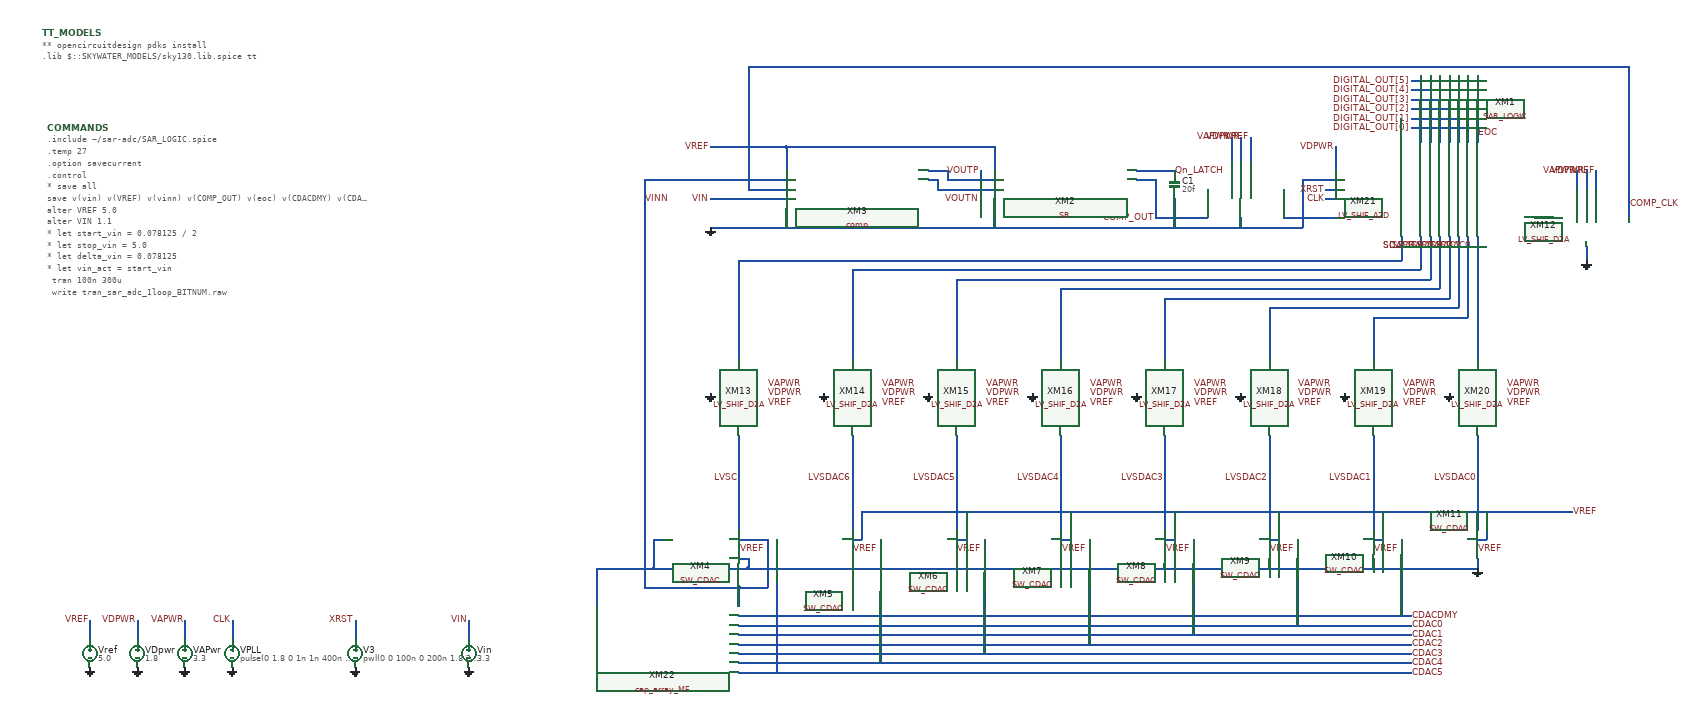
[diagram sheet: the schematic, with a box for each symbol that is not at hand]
v {xschem version=3.4.8RC file_version=1.3}
G {}
K {}
V {}
S {}
F {}
E {}
N 330 -310 330 -270 {
lab=VAPWR}
N 430 -310 430 -270 {
lab=CLK}
N 690 -310 690 -270 {
lab=XRST}
N 3050 -1100 3060 -1100 {
lab=SDAC0}
N 3030 -1100 3040 -1100 {
lab=SDAC1}
N 3010 -1100 3020 -1100 {
lab=SDAC2}
N 2990 -1100 3000 -1100 {
lab=SDAC3}
N 2970 -1100 2980 -1100 {
lab=SDAC4}
N 2950 -1100 2960 -1100 {
lab=SDAC5}
N 2930 -1100 2940 -1100 {
lab=SDAC6}
N 2890 -1100 2900 -1100 {
lab=SC}
N 930 -310 930 -270 {
lab=VIN}
N 2010 -1220 2010 -1200 {
lab=VOUTN}
N 2010 -1260 2010 -1240 {
lab=VOUTP}
N 230 -310 230 -270 {
lab=VDPWR}
N 130 -310 130 -270 {
lab=VREF}
N 2740 -1200 2760 -1200 {
lab=CLK}
N 2740 -1220 2760 -1220 {
lab=XRST}
N 1900 -1260 1940 -1260 {
lab=VOUTP}
N 1900 -1240 1920 -1240 {
lab=VOUTN}
N 1500 -320 2920 -320 {
lab=CDACDMY}
N 1500 -300 2920 -300 {
lab=CDAC0}
N 1500 -280 2920 -280 {
lab=CDAC1}
N 1500 -260 2920 -260 {
lab=CDAC2}
N 1500 -240 2920 -240 {
lab=CDAC3}
N 1500 -220 2920 -220 {
lab=CDAC4}
N 1500 -200 2920 -200 {
lab=CDAC5}
N 1740 -680 1740 -500 {
lab=LVSDAC6}
N 1960 -660 1960 -500 {
lab=LVSDAC5}
N 2180 -640 2180 -500 {
lab=LVSDAC4}
N 2400 -620 2400 -500 {
lab=LVSDAC3}
N 2620 -600 2620 -500 {
lab=LVSDAC2}
N 2840 -580 2840 -500 {
lab=LVSDAC1}
N 3060 -690 3060 -500 {
lab=LVSDAC0}
N 1500 -700 1500 -500 {
lab=LVSC}
N 1320 -480 1340 -480 {
lab=GND}
N 1320 -480 1320 -420 {
lab=GND}
N 1320 -420 1520 -420 {
lab=GND}
N 1520 -440 1520 -420 {
lab=GND}
N 1500 -440 1520 -440 {
lab=GND}
N 1500 -380 1500 -340 {
lab=VINN}
N 1300 -380 1500 -380 {
lab=VINN}
N 1300 -900 1300 -380 {
lab=VINN}
N 1500 -480 1560 -480 {
lab=VINN}
N 1560 -480 1560 -380 {
lab=VINN}
N 1500 -380 1560 -380 {
lab=VINN}
N 1520 -1220 1600 -1220 {
lab=COMP_CLK}
N 1620 -1480 3380 -1480 {
lab=COMP_CLK}
N 3380 -1480 3380 -1160 {
lab=COMP_CLK}
N 2340 -1240 2380 -1240 {
lab=COMP_OUT}
N 2380 -1240 2380 -1160 {
lab=COMP_OUT}
N 2340 -1260 2420 -1260 {
lab=Qn_LATCH}
N 1760 -540 3260 -540 {
lab=VREF}
N 1740 -480 1760 -480 {
lab=VREF}
N 1760 -540 1760 -480 {
lab=VREF}
N 1960 -480 1980 -480 {
lab=VREF}
N 1980 -540 1980 -480 {
lab=VREF}
N 2180 -480 2200 -480 {
lab=VREF}
N 2200 -540 2200 -480 {
lab=VREF}
N 2400 -480 2420 -480 {
lab=VREF}
N 2420 -540 2420 -480 {
lab=VREF}
N 2620 -480 2640 -480 {
lab=VREF}
N 2640 -540 2640 -480 {
lab=VREF}
N 2840 -480 2860 -480 {
lab=VREF}
N 2860 -540 2860 -480 {
lab=VREF}
N 3060 -480 3080 -480 {
lab=VREF}
N 3080 -540 3080 -480 {
lab=VREF}
N 1940 -1260 1940 -1240 {
lab=VOUTP}
N 2020 -480 2020 -240 {
lab=CDAC3}
N 1800 -480 1800 -220 {
lab=CDAC4}
N 1580 -480 1580 -200 {
lab=CDAC5}
N 2940 -1460 2940 -1320 {
lab=DIGITAL_OUT[5]}
N 2960 -1460 2960 -1320 {
lab=DIGITAL_OUT[4]}
N 2980 -1460 2980 -1320 {
lab=DIGITAL_OUT[3]}
N 3000 -1460 3000 -1320 {
lab=DIGITAL_OUT[2]}
N 3020 -1460 3020 -1320 {
lab=DIGITAL_OUT[1]}
N 3040 -1460 3040 -1320 {
lab=DIGITAL_OUT[0]}
N 3060 -1460 3060 -1320 {
lab=EOC}
N 1920 -1240 1920 -1220 {
lab=VOUTN}
N 1920 -1220 2040 -1220 {
lab=VOUTN}
N 1940 -1240 2040 -1240 {
lab=VOUTP}
N 2760 -1310 2760 -1260 {lab=VDPWR}
N 2040 -1310 2040 -1260 {lab=VREF}
N 1600 -1310 1600 -1260 {lab=VREF}
N 1590 -1140 2590 -1140 {lab=GND}
N 2690 -1240 2760 -1240 {lab=GND}
N 2420 -1200 2420 -1140 {lab=GND}
N 2040 -1200 2040 -1140 {lab=GND}
N 1600 -1180 1600 -1140 {lab=GND}
N 1520 -420 3060 -420 {lab=GND}
N 3060 -440 3060 -420 {lab=GND}
N 1740 -440 1740 -420 {lab=GND}
N 1960 -440 1960 -420 {lab=GND}
N 2180 -440 2180 -420 {lab=GND}
N 2400 -440 2400 -420 {lab=GND}
N 2620 -440 2620 -420 {lab=GND}
N 1440 -1310 1580 -1310 {lab=VREF}
N 1490 -1200 1600 -1200 {lab=VIN}
N 1440 -1200 1490 -1200 {lab=VIN}
N 1440 -1140 1590 -1140 {lab=GND}
N 1200 -420 1320 -420 {lab=GND}
N 1200 -420 1200 -340 {lab=GND}
N 1580 -1310 1600 -1310 {lab=VREF}
N 1600 -1310 2040 -1310 {lab=VREF}
N 3180 -1160 3220 -1160 {lab=#net1}
N 3060 -700 3060 -690 {lab=LVSDAC0}
N 2840 -700 2840 -580 {lab=LVSDAC1}
N 2620 -700 2620 -600 {lab=LVSDAC2}
N 2400 -700 2400 -620 {lab=LVSDAC3}
N 2180 -700 2180 -640 {lab=LVSDAC4}
N 1960 -700 1960 -660 {lab=LVSDAC5}
N 1740 -700 1740 -680 {lab=LVSDAC6}
N 1500 -1070 1500 -860 {lab=SC}
N 1500 -1070 2900 -1070 {lab=SC}
N 2900 -1120 2900 -1070 {lab=SC}
N 1740 -1050 1740 -860 {lab=SDAC6}
N 1740 -1050 2940 -1050 {lab=SDAC6}
N 2940 -1120 2940 -1050 {lab=SDAC6}
N 1960 -1030 1960 -860 {lab=SDAC5}
N 1960 -1030 2960 -1030 {lab=SDAC5}
N 2960 -1120 2960 -1030 {lab=SDAC5}
N 2180 -1010 2180 -860 {lab=SDAC4}
N 2180 -1010 2980 -1010 {lab=SDAC4}
N 2980 -1120 2980 -1010 {lab=SDAC4}
N 2400 -990 2400 -860 {lab=SDAC3}
N 2400 -990 3000 -990 {lab=SDAC3}
N 3000 -1120 3000 -990 {lab=SDAC3}
N 2620 -970 2620 -860 {lab=SDAC2}
N 2620 -970 3020 -970 {lab=SDAC2}
N 3020 -1120 3020 -970 {lab=SDAC2}
N 2840 -950 2840 -860 {lab=SDAC1}
N 2840 -950 3040 -950 {lab=SDAC1}
N 3040 -1120 3040 -950 {lab=SDAC1}
N 3060 -1120 3060 -860 {lab=SDAC0}
N 1300 -1240 1300 -900 {lab=VINN}
N 1300 -1240 1600 -1240 {lab=VINN}
N 1520 -1480 1520 -1220 {lab=COMP_CLK}
N 1520 -1480 1620 -1480 {lab=COMP_CLK}
N 2690 -1240 2690 -1140 {lab=GND}
N 2590 -1140 2690 -1140 {lab=GND}
N 2650 -1220 2650 -1160 {lab=#net2}
N 2650 -1160 2760 -1160 {lab=#net2}
N 2490 -1220 2490 -1160 {lab=COMP_OUT}
N 2380 -1160 2490 -1160 {lab=COMP_OUT}
N 2540 -1330 2540 -1280 {lab=VAPWR}
N 2560 -1330 2560 -1280 {lab=VDPWR}
N 2580 -1330 2580 -1280 {lab=VREF}
N 3270 -1260 3270 -1220 {lab=VAPWR}
N 3290 -1260 3290 -1220 {lab=VDPWR}
N 3310 -1260 3310 -1220 {lab=VREF}
N 2560 -1160 2560 -1140 {lab=GND}
N 3290 -1100 3290 -1070 {lab=GND}
N 2920 -1350 3040 -1350 {lab=DIGITAL_OUT[0]}
N 2920 -1370 3020 -1370 {lab=DIGITAL_OUT[1]}
N 2920 -1390 3000 -1390 {lab=DIGITAL_OUT[2]}
N 2920 -1410 2980 -1410 {lab=DIGITAL_OUT[3]}
N 2920 -1430 2960 -1430 {lab=DIGITAL_OUT[4]}
N 2920 -1450 2940 -1450 {lab=DIGITAL_OUT[5]}
N 2460 -480 2460 -280 {lab=CDAC1}
N 2240 -480 2240 -260 {lab=CDAC2}
N 2680 -480 2680 -300 {lab=CDAC0}
N 2900 -480 2900 -320 {lab=CDACDMY}
N 2840 -440 2840 -420 {lab=GND}
C {devices/vsource.sym} 330 -240 0 0 {name=VAPwr value=3.3 savecurrent=false}
C {devices/gnd.sym} 430 -210 0 0 {name=l2 lab=GND}
C {devices/gnd.sym} 330 -210 0 0 {name=l3 lab=GND}
C {devices/simulator_commands_shown.sym} 40 -1350 0 0 {name=COMMANDS
simulator=ngspice
only_toplevel=false 
value=".include ~/sar-adc/SAR_LOGIC.spice
.temp 27
.option savecurrent
.control
* save all
save v(vin) v(VREF) v(vinn) v(COMP_OUT) v(eoc) v(CDACDMY) v(CDAC0) v(CDAC1) v(CDAC2) v(CDAC3) v(CDAC4) v(CDAC5) v(digital_out[5]) v(digital_out[4]) v(digital_out[3]) v(digital_out[2]) v(digital_out[1]) v(digital_out[0])

alter VREF 5.0
alter VIN  1.1

* let start_vin = 0.078125 / 2
* let stop_vin = 5.0
* let delta_vin = 0.078125
* let vin_act = start_vin

	tran 100n 300u
	write tran_sar_adc_1loop_BITNUM.raw
	meas tran vin FIND v(VIN) WHEN v(EOC)=0.9 FALL=LAST
	meas tran vinn FIND v(vinn) WHEN v(EOC)=0.9 FALL=LAST
	meas tran vout5 FIND v(DIGITAL_OUT[5]) WHEN v(EOC)=0.9 FALL=LAST
	meas tran vout4 FIND v(DIGITAL_OUT[4]) WHEN v(EOC)=0.9 FALL=LAST
	meas tran vout3 FIND v(DIGITAL_OUT[3]) WHEN v(EOC)=0.9 FALL=LAST
	meas tran vout2 FIND v(DIGITAL_OUT[2]) WHEN v(EOC)=0.9 FALL=LAST
	meas tran vout1 FIND v(DIGITAL_OUT[1]) WHEN v(EOC)=0.9 FALL=LAST
	meas tran vout0 FIND v(DIGITAL_OUT[0]) WHEN v(EOC)=0.9 FALL=LAST
	print vin >> tran_sar_adc_1loop_out_typ_BITNUM.txt
	print vout5 >> tran_sar_adc_1loop_out_typ_BITNUM.txt
	print vout4 >> tran_sar_adc_1loop_out_typ_BITNUM.txt
	print vout3 >> tran_sar_adc_1loop_out_typ_BITNUM.txt
	print vout2 >> tran_sar_adc_1loop_out_typ_BITNUM.txt
	print vout1 >> tran_sar_adc_1loop_out_typ_BITNUM.txt
	print vout0 >> tran_sar_adc_1loop_out_typ_BITNUM.txt

.endc
"}
C {devices/lab_pin.sym} 430 -310 0 0 {name=p2 sig_type=std_logic lab=CLK}
C {devices/lab_pin.sym} 690 -310 0 0 {name=p9 sig_type=std_logic lab=XRST}
C {devices/gnd.sym} 690 -210 0 0 {name=l1 lab=GND}
C {devices/lab_pin.sym} 3050 -1100 3 0 {name=p10 sig_type=std_logic lab=SDAC0}
C {devices/lab_pin.sym} 3030 -1100 3 0 {name=p11 sig_type=std_logic lab=SDAC1}
C {devices/lab_pin.sym} 3010 -1100 3 0 {name=p12 sig_type=std_logic lab=SDAC2}
C {devices/lab_pin.sym} 2990 -1100 3 0 {name=p13 sig_type=std_logic lab=SDAC3}
C {devices/lab_pin.sym} 2970 -1100 3 0 {name=p14 sig_type=std_logic lab=SDAC4}
C {devices/lab_pin.sym} 2950 -1100 3 0 {name=p15 sig_type=std_logic lab=SDAC5}
C {devices/lab_pin.sym} 2930 -1100 3 0 {name=p16 sig_type=std_logic lab=SDAC6}
C {devices/lab_pin.sym} 2890 -1100 3 0 {name=p19 sig_type=std_logic lab=SC}
C {devices/lab_pin.sym} 3380 -1190 2 0 {name=p20 sig_type=std_logic lab=COMP_CLK}
C {devices/gnd.sym} 1440 -1140 0 1 {name=l19 lab=GND}
C {devices/lab_pin.sym} 930 -310 2 1 {name=p25 sig_type=std_logic lab=VIN}
C {devices/gnd.sym} 930 -210 0 0 {name=l22 lab=GND}
C {devices/vsource.sym} 930 -240 0 0 {name=Vin value=3.3 savecurrent=false}
C {devices/lab_pin.sym} 1440 -1200 0 0 {name=p26 sig_type=std_logic lab=VIN}
C {devices/lab_pin.sym} 2010 -1200 0 0 {name=p27 sig_type=std_logic lab=VOUTN}
C {devices/lab_pin.sym} 2010 -1260 2 1 {name=p28 sig_type=std_logic lab=VOUTP}
C {devices/lab_pin.sym} 2920 -260 0 1 {name=p29 sig_type=std_logic lab=CDAC2}
C {devices/lab_pin.sym} 2920 -280 0 1 {name=p30 sig_type=std_logic lab=CDAC1}
C {devices/lab_pin.sym} 2920 -300 0 1 {name=p31 sig_type=std_logic lab=CDAC0}
C {devices/lab_pin.sym} 2920 -320 0 1 {name=p32 sig_type=std_logic lab=CDACDMY}
C {devices/lab_pin.sym} 2920 -240 0 1 {name=p33 sig_type=std_logic lab=CDAC3}
C {devices/lab_pin.sym} 2920 -220 0 1 {name=p34 sig_type=std_logic lab=CDAC4}
C {devices/lab_pin.sym} 2920 -200 0 1 {name=p35 sig_type=std_logic lab=CDAC5}
C {devices/lab_pin.sym} 1300 -1200 0 1 {name=p36 sig_type=std_logic lab=VINN}
C {devices/lab_pin.sym} 2420 -1260 2 0 {name=p38 sig_type=std_logic lab=Qn_LATCH}
C {devices/lab_pin.sym} 2380 -1160 0 0 {name=p39 sig_type=std_logic lab=COMP_OUT}
C {devices/lab_pin.sym} 2920 -1450 0 0 {name=p18 sig_type=std_logic lab=DIGITAL_OUT[5]}
C {devices/lab_pin.sym} 2920 -1430 0 0 {name=p21 sig_type=std_logic lab=DIGITAL_OUT[4]}
C {devices/lab_pin.sym} 2920 -1410 0 0 {name=p40 sig_type=std_logic lab=DIGITAL_OUT[3]}
C {devices/lab_pin.sym} 2920 -1390 0 0 {name=p41 sig_type=std_logic lab=DIGITAL_OUT[2]}
C {devices/lab_pin.sym} 2920 -1370 0 0 {name=p42 sig_type=std_logic lab=DIGITAL_OUT[1]}
C {devices/lab_pin.sym} 2920 -1350 0 0 {name=p43 sig_type=std_logic lab=DIGITAL_OUT[0]}
C {devices/lab_pin.sym} 3060 -1340 2 0 {name=p17 sig_type=std_logic lab=EOC}
C {devices/vsource.sym} 130 -240 0 0 {name=Vref value=5.0 savecurrent=false}
C {devices/gnd.sym} 130 -210 0 0 {name=l23 lab=GND}
C {devices/code.sym} 30 -1550 0 0 {name=TT_MODELS
only_toplevel=true
format="tcleval( @value )"
value="
** opencircuitdesign pdks install
.lib $::SKYWATER_MODELS/sky130.lib.spice tt
"
spice_ignore=false}
C {devices/lab_pin.sym} 330 -310 0 0 {name=p44 sig_type=std_logic lab=VAPWR}
C {devices/vsource.sym} 230 -240 0 0 {name=VDpwr value=1.8 savecurrent=false}
C {devices/gnd.sym} 230 -210 0 0 {name=l12 lab=GND
value=1.8}
C {devices/lab_pin.sym} 230 -310 0 0 {name=p45 sig_type=std_logic lab=VDPWR}
C {devices/lab_pin.sym} 1440 -1310 2 1 {name=p47 sig_type=std_logic lab=VREF}
C {devices/lab_pin.sym} 130 -310 0 0 {name=p48 sig_type=std_logic lab=VREF}
C {devices/lab_pin.sym} 1500 -460 2 0 {name=p1 sig_type=std_logic lab=VREF}
C {devices/lab_pin.sym} 1740 -460 2 0 {name=p3 sig_type=std_logic lab=VREF}
C {devices/lab_pin.sym} 1960 -460 2 0 {name=p4 sig_type=std_logic lab=VREF}
C {devices/lab_pin.sym} 2180 -460 2 0 {name=p6 sig_type=std_logic lab=VREF}
C {devices/lab_pin.sym} 2400 -460 2 0 {name=p8 sig_type=std_logic lab=VREF}
C {devices/lab_pin.sym} 2620 -460 2 0 {name=p22 sig_type=std_logic lab=VREF}
C {devices/lab_pin.sym} 2840 -460 2 0 {name=p23 sig_type=std_logic lab=VREF}
C {devices/lab_pin.sym} 3060 -460 2 0 {name=p24 sig_type=std_logic lab=VREF}
C {SR.sym} 2190 -1230 0 0 {name=XM2
spiceprefix=X
}
C {SAR_LOGIC.sym} 2970 -1210 0 0 {name=XM1 prefix=SAR_LOGIC}
C {SW_CDAC.sym} 1500 -500 0 1 {name=XM4
spiceprefix=X}
C {SW_CDAC.sym} 1740 -500 0 1 {name=XM5
spiceprefix=X}
C {SW_CDAC.sym} 1960 -500 0 1 {name=XM6
spiceprefix=X}
C {SW_CDAC.sym} 2180 -500 0 1 {name=XM7
spiceprefix=X}
C {SW_CDAC.sym} 2400 -500 0 1 {name=XM8
spiceprefix=X}
C {SW_CDAC.sym} 2620 -500 0 1 {name=XM9
spiceprefix=X}
C {SW_CDAC.sym} 2840 -500 0 1 {name=XM10
spiceprefix=X}
C {SW_CDAC.sym} 3060 -500 0 1 {name=XM11
spiceprefix=X}
C {comp.sym} 1750 -1220 0 0 {name=XM3
spiceprefix=X}
C {devices/lab_pin.sym} 3260 -540 2 0 {name=p46 sig_type=std_logic lab=VREF}
C {LV_SHIF_D2A.sym} 3360 -1100 0 0 {name=XM12
spiceprefix=X
}
C {LV_SHIF_D2A.sym} 1440 -720 1 0 {name=XM13
spiceprefix=X
}
C {LV_SHIF_D2A.sym} 1680 -720 1 0 {name=XM14
spiceprefix=X
}
C {LV_SHIF_D2A.sym} 1900 -720 1 0 {name=XM15
spiceprefix=X
}
C {LV_SHIF_D2A.sym} 2120 -720 1 0 {name=XM16
spiceprefix=X
}
C {LV_SHIF_D2A.sym} 2340 -720 1 0 {name=XM17
spiceprefix=X
}
C {LV_SHIF_D2A.sym} 2560 -720 1 0 {name=XM18
spiceprefix=X
}
C {LV_SHIF_D2A.sym} 2780 -720 1 0 {name=XM19
spiceprefix=X
}
C {LV_SHIF_D2A.sym} 3000 -720 1 0 {name=XM20
spiceprefix=X
}
C {LV_SHIF_A2D.sym} 2630 -1160 0 0 {name=XM21
spiceprefix=X
}
C {devices/lab_pin.sym} 2760 -1310 0 0 {name=p61 sig_type=std_logic lab=VDPWR}
C {devices/lab_pin.sym} 2580 -1330 3 1 {name=p62 sig_type=std_logic lab=VREF}
C {devices/lab_pin.sym} 3290 -1260 3 1 {name=p63 sig_type=std_logic lab=VDPWR}
C {devices/lab_pin.sym} 3310 -1260 3 1 {name=p64 sig_type=std_logic lab=VREF}
C {devices/lab_pin.sym} 3270 -1260 3 1 {name=p65 sig_type=std_logic lab=VAPWR}
C {devices/lab_pin.sym} 3120 -770 2 0 {name=p75 sig_type=std_logic lab=VREF}
C {devices/lab_pin.sym} 3120 -790 0 1 {name=p76 sig_type=std_logic lab=VDPWR}
C {devices/lab_pin.sym} 3120 -810 0 1 {name=p77 sig_type=std_logic lab=VAPWR}
C {devices/lab_pin.sym} 2900 -770 2 0 {name=p78 sig_type=std_logic lab=VREF}
C {devices/lab_pin.sym} 2900 -790 0 1 {name=p79 sig_type=std_logic lab=VDPWR}
C {devices/lab_pin.sym} 2900 -810 0 1 {name=p80 sig_type=std_logic lab=VAPWR}
C {devices/lab_pin.sym} 2680 -770 2 0 {name=p81 sig_type=std_logic lab=VREF}
C {devices/lab_pin.sym} 2680 -790 0 1 {name=p82 sig_type=std_logic lab=VDPWR}
C {devices/lab_pin.sym} 2680 -810 0 1 {name=p83 sig_type=std_logic lab=VAPWR}
C {devices/lab_pin.sym} 2460 -770 2 0 {name=p84 sig_type=std_logic lab=VREF}
C {devices/lab_pin.sym} 2460 -790 0 1 {name=p85 sig_type=std_logic lab=VDPWR}
C {devices/lab_pin.sym} 2460 -810 0 1 {name=p86 sig_type=std_logic lab=VAPWR}
C {devices/lab_pin.sym} 2240 -770 2 0 {name=p87 sig_type=std_logic lab=VREF}
C {devices/lab_pin.sym} 2240 -790 0 1 {name=p88 sig_type=std_logic lab=VDPWR}
C {devices/lab_pin.sym} 2240 -810 0 1 {name=p89 sig_type=std_logic lab=VAPWR}
C {devices/lab_pin.sym} 2020 -770 2 0 {name=p90 sig_type=std_logic lab=VREF}
C {devices/lab_pin.sym} 2020 -790 0 1 {name=p91 sig_type=std_logic lab=VDPWR}
C {devices/lab_pin.sym} 2020 -810 0 1 {name=p92 sig_type=std_logic lab=VAPWR}
C {devices/lab_pin.sym} 1800 -770 2 0 {name=p93 sig_type=std_logic lab=VREF}
C {devices/lab_pin.sym} 1800 -790 0 1 {name=p94 sig_type=std_logic lab=VDPWR}
C {devices/lab_pin.sym} 1800 -810 0 1 {name=p95 sig_type=std_logic lab=VAPWR}
C {devices/lab_pin.sym} 1560 -770 2 0 {name=p96 sig_type=std_logic lab=VREF}
C {devices/lab_pin.sym} 1560 -790 0 1 {name=p97 sig_type=std_logic lab=VDPWR}
C {devices/lab_pin.sym} 1560 -810 0 1 {name=p98 sig_type=std_logic lab=VAPWR}
C {devices/lab_pin.sym} 2560 -1330 3 1 {name=p5 sig_type=std_logic lab=VDPWR}
C {devices/lab_pin.sym} 2540 -1330 3 1 {name=p7 sig_type=std_logic lab=VAPWR}
C {devices/lab_pin.sym} 2740 -1200 0 0 {name=p49 sig_type=std_logic lab=CLK}
C {devices/lab_pin.sym} 2740 -1220 0 0 {name=p50 sig_type=std_logic lab=XRST}
C {devices/gnd.sym} 3290 -1070 0 1 {name=l4 lab=GND}
C {devices/gnd.sym} 3060 -420 0 1 {name=l5 lab=GND}
C {devices/gnd.sym} 1440 -790 0 1 {name=l6 lab=GND}
C {devices/gnd.sym} 1680 -790 0 1 {name=l7 lab=GND}
C {devices/gnd.sym} 1900 -790 0 1 {name=l8 lab=GND}
C {devices/gnd.sym} 2120 -790 0 1 {name=l9 lab=GND}
C {devices/gnd.sym} 2340 -790 0 1 {name=l10 lab=GND}
C {devices/gnd.sym} 2560 -790 0 1 {name=l11 lab=GND}
C {devices/gnd.sym} 2780 -790 0 1 {name=l13 lab=GND}
C {devices/gnd.sym} 3000 -790 0 1 {name=l14 lab=GND}
C {devices/lab_pin.sym} 1500 -610 0 0 {name=p37 sig_type=std_logic lab=LVSC}
C {devices/lab_pin.sym} 1740 -610 0 0 {name=p51 sig_type=std_logic lab=LVSDAC6}
C {devices/lab_pin.sym} 1960 -610 0 0 {name=p52 sig_type=std_logic lab=LVSDAC5}
C {devices/lab_pin.sym} 2180 -610 0 0 {name=p53 sig_type=std_logic lab=LVSDAC4}
C {devices/lab_pin.sym} 2400 -610 0 0 {name=p54 sig_type=std_logic lab=LVSDAC3}
C {devices/lab_pin.sym} 2620 -610 0 0 {name=p55 sig_type=std_logic lab=LVSDAC2}
C {devices/lab_pin.sym} 2840 -610 0 0 {name=p56 sig_type=std_logic lab=LVSDAC1}
C {devices/lab_pin.sym} 3060 -610 0 0 {name=p57 sig_type=std_logic lab=LVSDAC0}
C {cap_array_MF.sym} 1350 -270 0 0 {name=XM22
spiceprefix=X}
C {devices/vsource.sym} 430 -240 0 0 {name=VPLL value="pulse(0 1.8 0 1n 1n 400n 800n)" savecurrent=false}
C {devices/vsource.sym} 690 -240 0 0 {name=V3 value="pwl(0 0 100n 0 200n 1.8 200n 1.8)" savecurrent=false}
C {devices/capa.sym} 2420 -1230 0 0 {name=C1
m=1
value=20f
footprint=1206
device="ceramic capacitor"}
